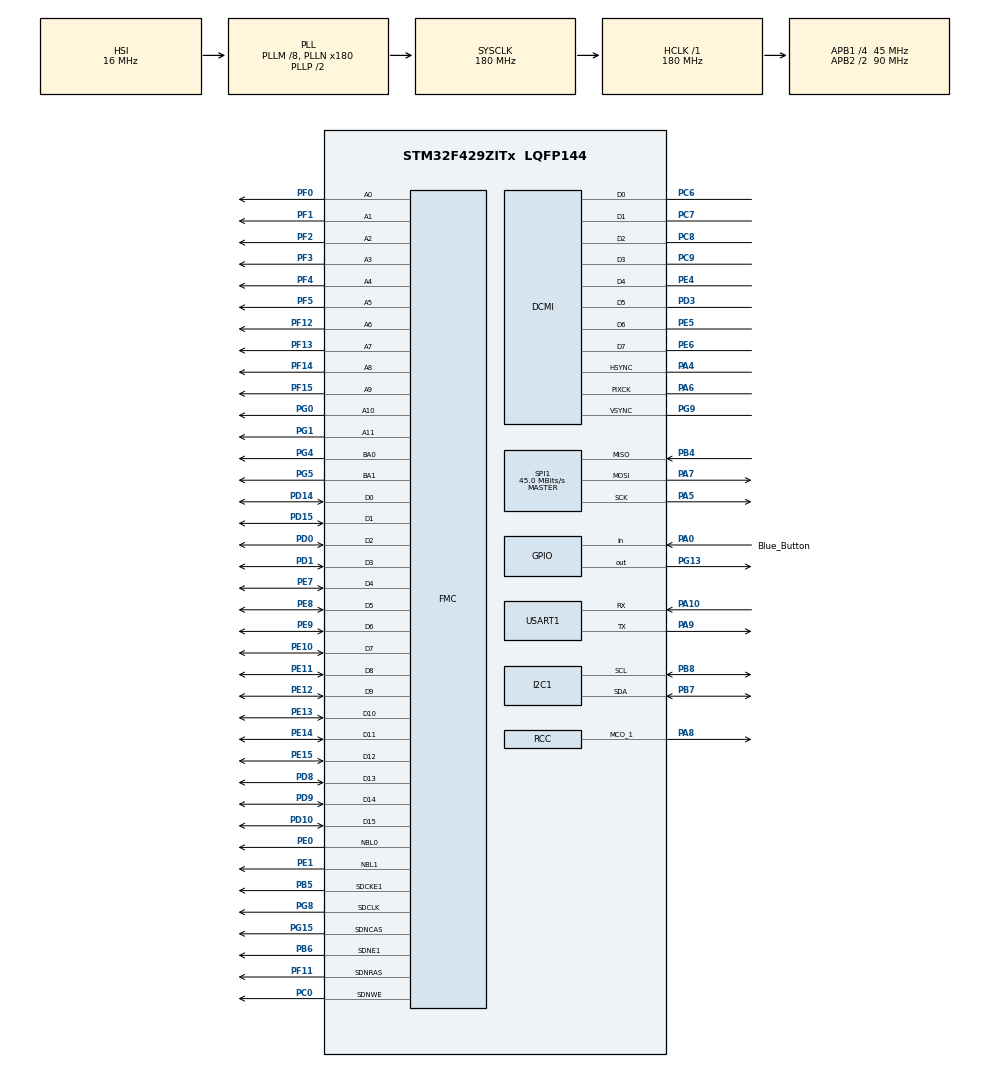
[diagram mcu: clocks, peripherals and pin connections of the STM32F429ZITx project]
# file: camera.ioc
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DCMI.HSPolarity=DCMI_HSPOLARITY_LOW
DCMI.JPEGMode=DCMI_JPEG_DISABLE
DCMI.PCKPolarity=DCMI_PCKPOLARITY_RISING
DCMI.VSPolarity=DCMI_VSPOLARITY_HIGH
Dma.DCMI.0.Direction=DMA_PERIPH_TO_MEMORY
Dma.DCMI.0.FIFOMode=DMA_FIFOMODE_DISABLE
Dma.DCMI.0.Instance=DMA2_Stream1
Dma.DCMI.0.MemDataAlignment=DMA_MDATAALIGN_WORD
Dma.DCMI.0.MemInc=DMA_MINC_ENABLE
Dma.DCMI.0.Mode=DMA_NORMAL
Dma.DCMI.0.PeriphDataAlignment=DMA_PDATAALIGN_WORD
Dma.DCMI.0.PeriphInc=DMA_PINC_DISABLE
Dma.DCMI.0.Priority=DMA_PRIORITY_LOW
Dma.Request0=DCMI
FMC.CASLatency1=FMC_SDRAM_CAS_LATENCY_3
FMC.ExitSelfRefreshDelay1=7
FMC.LoadToActiveDelay1=2
FMC.RCDDelay1=2
FMC.RPDelay1=2
FMC.RPDelay2=2
FMC.ReadPipeDelay1=FMC_SDRAM_RPIPE_DELAY_1
FMC.ReadPipeDelay2=FMC_SDRAM_RPIPE_DELAY_1
FMC.RowCycleDelay1=7
FMC.RowCycleDelay2=7
FMC.SDClockPeriod1=FMC_SDRAM_CLOCK_PERIOD_2
FMC.SDClockPeriod2=FMC_SDRAM_CLOCK_PERIOD_2
FMC.SelfRefreshTime1=4
FMC.WriteRecoveryTime1=3
Mcu.Family=STM32F4
Mcu.Name=STM32F429ZITx
Mcu.Package=LQFP144
NVIC.DCMI_IRQn=true\:0\:0\:false\:false\:true\:true
NVIC.DMA2_Stream1_IRQn=true\:0\:0\:false\:false\:true\:false
NVIC.PriorityGroup=NVIC_PRIORITYGROUP_4
PA0/WKUP.GPIO_Label=Blue_Button
PA0/WKUP.GPIO_PuPd=GPIO_PULLDOWN
PA0/WKUP.Signal=GPIO_Input
PA10.Mode=Asynchronous
PA10.Signal=USART1_RX
PA4.Mode=Slave_8_bits_External_Synchro
PA4.Signal=DCMI_HSYNC
PA5.Mode=Full_Duplex_Master
PA5.Signal=SPI1_SCK
PA6.Mode=Slave_8_bits_External_Synchro
PA6.Signal=DCMI_PIXCK
PA7.Mode=Full_Duplex_Master
PA7.Signal=SPI1_MOSI
PA8.Mode=Clock-out-1
PA8.Signal=RCC_MCO_1
PA9.Mode=Asynchronous
PA9.Signal=USART1_TX
PB4.Mode=Full_Duplex_Master
PB4.Signal=SPI1_MISO
PB5.Mode=SdramChipSelect2_1
PB5.Signal=FMC_SDCKE1
PB6.Mode=SdramChipSelect2_1
PB6.Signal=FMC_SDNE1
PB7.Mode=I2C
PB7.Signal=I2C1_SDA
PB8.Mode=I2C
PB8.Signal=I2C1_SCL
PC0.Signal=FMC_SDNWE
PC6.Mode=Slave_8_bits_External_Synchro
PC6.Signal=DCMI_D0
PC7.Mode=Slave_8_bits_External_Synchro
PC7.Signal=DCMI_D1
PC8.Mode=Slave_8_bits_External_Synchro
PC8.Signal=DCMI_D2
PC9.Mode=Slave_8_bits_External_Synchro
PC9.Signal=DCMI_D3
PD0.Signal=FMC_D2_DA2
PD1.Signal=FMC_D3_DA3
PD10.Signal=FMC_D15_DA15
PD14.Signal=FMC_D0_DA0
PD15.Signal=FMC_D1_DA1
PD3.Mode=Slave_8_bits_External_Synchro
PD3.Signal=DCMI_D5
PD8.Signal=FMC_D13_DA13
PD9.Signal=FMC_D14_DA14
PE0.Signal=FMC_NBL0
PE1.Signal=FMC_NBL1
PE10.Signal=FMC_D7_DA7
PE11.Signal=FMC_D8_DA8
PE12.Signal=FMC_D9_DA9
PE13.Signal=FMC_D10_DA10
PE14.Signal=FMC_D11_DA11
PE15.Signal=FMC_D12_DA12
PE4.Mode=Slave_8_bits_External_Synchro
PE4.Signal=DCMI_D4
PE5.Mode=Slave_8_bits_External_Synchro
PE5.Signal=DCMI_D6
PE6.Mode=Slave_8_bits_External_Synchro
PE6.Signal=DCMI_D7
PE7.Signal=FMC_D4_DA4
PE8.Signal=FMC_D5_DA5
PE9.Signal=FMC_D6_DA6
PF0.Signal=FMC_A0
PF1.Signal=FMC_A1
PF11.Signal=FMC_SDNRAS
PF12.Signal=FMC_A6
PF13.Signal=FMC_A7
PF14.Signal=FMC_A8
PF15.Signal=FMC_A9
PF2.Signal=FMC_A2
PF3.Signal=FMC_A3
PF4.Signal=FMC_A4
PF5.Signal=FMC_A5
PG0.Signal=FMC_A10
PG1.Signal=FMC_A11
PG13.GPIO_PuPd=GPIO_NOPULL
PG13.Signal=GPIO_Output
PG15.Signal=FMC_SDNCAS
PG4.Signal=FMC_A14_BA0
PG5.Signal=FMC_A15_BA1
PG8.Signal=FMC_SDCLK
PG9.Mode=Slave_8_bits_External_Synchro
PG9.Signal=DCMI_VSYNC
ProjectManager.HeapSize=0x200
ProjectManager.StackSize=0x400
ProjectManager.TargetToolchain=TrueSTUDIO
RCC.48MHZClocksFreq_Value=90000000
RCC.AHBFreq_Value=180000000
RCC.APB1CLKDivider=RCC_HCLK_DIV4
RCC.APB1Freq_Value=45000000
RCC.APB1TimFreq_Value=90000000
RCC.APB2CLKDivider=RCC_HCLK_DIV2
RCC.APB2Freq_Value=90000000
RCC.APB2TimFreq_Value=180000000
RCC.CortexFreq_Value=180000000
RCC.HCLKFreq_Value=180000000
RCC.HSE_VALUE=25000000
RCC.HSI_VALUE=16000000
RCC.LSE_VALUE=32768
RCC.PLLM=8
RCC.PLLN=180
RCC.RCC_MCODiv1=RCC_MCODIV_2
RCC.SYSCLKFreq_VALUE=180000000
RCC.SYSCLKSource=RCC_SYSCLKSOURCE_PLLCLK
RCC.VCOOutputFreq_Value=360000000
SH.FMC_A0.0=FMC_A0,12b-sda1
SH.FMC_A1.0=FMC_A1,12b-sda1
SH.FMC_A10.0=FMC_A10,12b-sda1
SH.FMC_A11.0=FMC_A11,12b-sda1
SH.FMC_A14_BA0.0=FMC_BA0,FourSdramBanks1
SH.FMC_A15_BA1.0=FMC_BA1,FourSdramBanks1
SH.FMC_A2.0=FMC_A2,12b-sda1
SH.FMC_A3.0=FMC_A3,12b-sda1
SH.FMC_A4.0=FMC_A4,12b-sda1
SH.FMC_A5.0=FMC_A5,12b-sda1
SH.FMC_A6.0=FMC_A6,12b-sda1
SH.FMC_A7.0=FMC_A7,12b-sda1
SH.FMC_A8.0=FMC_A8,12b-sda1
SH.FMC_A9.0=FMC_A9,12b-sda1
SH.FMC_D0_DA0.0=FMC_D0,sd-16b-d1
SH.FMC_D10_DA10.0=FMC_D10,sd-16b-d1
SH.FMC_D11_DA11.0=FMC_D11,sd-16b-d1
SH.FMC_D12_DA12.0=FMC_D12,sd-16b-d1
SH.FMC_D13_DA13.0=FMC_D13,sd-16b-d1
SH.FMC_D14_DA14.0=FMC_D14,sd-16b-d1
SH.FMC_D15_DA15.0=FMC_D15,sd-16b-d1
SH.FMC_D1_DA1.0=FMC_D1,sd-16b-d1
SH.FMC_D2_DA2.0=FMC_D2,sd-16b-d1
SH.FMC_D3_DA3.0=FMC_D3,sd-16b-d1
SH.FMC_D4_DA4.0=FMC_D4,sd-16b-d1
SH.FMC_D5_DA5.0=FMC_D5,sd-16b-d1
SH.FMC_D6_DA6.0=FMC_D6,sd-16b-d1
SH.FMC_D7_DA7.0=FMC_D7,sd-16b-d1
SH.FMC_D8_DA8.0=FMC_D8,sd-16b-d1
SH.FMC_D9_DA9.0=FMC_D9,sd-16b-d1
SH.FMC_NBL0.0=FMC_NBL0,Sd2ByteEnable1
SH.FMC_NBL1.0=FMC_NBL1,Sd2ByteEnable1
SH.FMC_SDCLK.0=FMC_SDCLK,12b-sda1
SH.FMC_SDNCAS.0=FMC_SDNCAS,12b-sda1
SH.FMC_SDNRAS.0=FMC_SDNRAS,12b-sda1
SH.FMC_SDNWE.0=FMC_SDNWE,12b-sda1
SPI1.CalculateBaudRate=45.0 MBits/s
SPI1.Direction=SPI_DIRECTION_2LINES
SPI1.Mode=SPI_MODE_MASTER
SPI1.VirtualType=VM_MASTER
USART1.VirtualMode=VM_ASYNC
board=custom

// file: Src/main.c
/* USER CODE BEGIN Header */
/**
  ******************************************************************************
  * @file           : main.c
  * @brief          : Main program body
  ******************************************************************************
  ** This notice applies to any and all portions of this file
  * that are not between comment pairs USER CODE BEGIN and
  * USER CODE END. Other portions of this file, whether
  * inserted by the user or by software development tools
  * are owned by their respective copyright owners.
  *
  * COPYRIGHT(c) 2018 STMicroelectronics
  *
  * Redistribution and use in source and binary forms, with or without modification,
  * are permitted provided that the following conditions are met:
  *   1. Redistributions of source code must retain the above copyright notice,
  *      this list of conditions and the following disclaimer.
  *   2. Redistributions in binary form must reproduce the above copyright notice,
  *      this list of conditions and the following disclaimer in the documentation
  *      and/or other materials provided with the distribution.
  *   3. Neither the name of STMicroelectronics nor the names of its contributors
  *      may be used to endorse or promote products derived from this software
  *      without specific prior written permission.
  *
  * THIS SOFTWARE IS PROVIDED BY THE COPYRIGHT HOLDERS AND CONTRIBUTORS "AS IS"
  * AND ANY EXPRESS OR IMPLIED WARRANTIES, INCLUDING, BUT NOT LIMITED TO, THE
  * IMPLIED WARRANTIES OF MERCHANTABILITY AND FITNESS FOR A PARTICULAR PURPOSE ARE
  * DISCLAIMED. IN NO EVENT SHALL THE COPYRIGHT HOLDER OR CONTRIBUTORS BE LIABLE
  * FOR ANY DIRECT, INDIRECT, INCIDENTAL, SPECIAL, EXEMPLARY, OR CONSEQUENTIAL
  * DAMAGES (INCLUDING, BUT NOT LIMITED TO, PROCUREMENT OF SUBSTITUTE GOODS OR
  * SERVICES; LOSS OF USE, DATA, OR PROFITS; OR BUSINESS INTERRUPTION) HOWEVER
  * CAUSED AND ON ANY THEORY OF LIABILITY, WHETHER IN CONTRACT, STRICT LIABILITY,
  * OR TORT (INCLUDING NEGLIGENCE OR OTHERWISE) ARISING IN ANY WAY OUT OF THE USE
  * OF THIS SOFTWARE, EVEN IF ADVISED OF THE POSSIBILITY OF SUCH DAMAGE.
  *
  ******************************************************************************
  */
/* USER CODE END Header */

#include "main.h"

/* USER CODE BEGIN Includes */
#include "ov7670.h"
#include "spi.h"
#include "nrf.h"
#include <string.h>
#include <stdio.h>
#include <stdlib.h>
#include <math.h>
#include "arm_math.h"
#include "parameter.h"
#include "weights.h"
#include "arm_nnfunctions.h"
/* USER CODE END Includes */

/* USER CODE BEGIN PTD */
#define INPUT_MEAN_SHIFT {125,123,114}
#define INPUT_RIGHT_SHIFT {8,8,8}
#define __SSAT(ARG1,ARG2) \
__extension__ \
({                          \
  int32_t __RES, __ARG1 = (ARG1); \
  __ASM ("ssat %0, %1, %2" : "=r" (__RES) :  "I" (ARG2), "r" (__ARG1) ); \
  __RES; \
 })
/* USER CODE END PTD */

DCMI_HandleTypeDef hdcmi;
DMA_HandleTypeDef hdma_dcmi;

I2C_HandleTypeDef hi2c1;

SPI_HandleTypeDef hspi1;

UART_HandleTypeDef huart1;

SDRAM_HandleTypeDef hsdram1;

/* USER CODE BEGIN PV */

static q7_t conv1_wt[CONV1_IN_CH*CONV1_KER_DIM*CONV1_KER_DIM*CONV1_OUT_CH] = CONV1_WT;
static q7_t conv1_bias[CONV1_OUT_CH] = CONV1_BIAS;

static q7_t conv2_wt[CONV2_IN_CH*CONV2_KER_DIM*CONV2_KER_DIM*CONV2_OUT_CH] = CONV2_WT;
static q7_t conv2_bias[CONV2_OUT_CH] = CONV2_BIAS;

static q7_t conv3_wt[CONV3_IN_CH*CONV3_KER_DIM*CONV3_KER_DIM*CONV3_OUT_CH] = CONV3_WT;
static q7_t conv3_bias[CONV3_OUT_CH] = CONV3_BIAS;

static q7_t ip1_wt[IP1_IN_DIM*IP1_OUT_DIM] = IP1_WT;
static q7_t ip1_bias[IP1_OUT_DIM] = IP1_BIAS;

q7_t input_data[DATA_OUT_CH*DATA_OUT_DIM*DATA_OUT_DIM];
q7_t output_data[IP1_OUT_DIM];

q7_t col_buffer[3200];
q7_t scratch_buffer[40960];
float floater_data[10];

void run_nn() {

  q7_t* buffer1 = scratch_buffer;
  q7_t* buffer2 = buffer1 + 32768;
  arm_convolve_HWC_q7_RGB(input_data, CONV1_IN_DIM, CONV1_IN_CH, conv1_wt, CONV1_OUT_CH, CONV1_KER_DIM, CONV1_PAD, CONV1_STRIDE, conv1_bias, CONV1_BIAS_LSHIFT, CONV1_OUT_RSHIFT, buffer1, CONV1_OUT_DIM, (q15_t*)col_buffer, NULL);
  arm_maxpool_q7_HWC(buffer1, POOL1_IN_DIM, POOL1_IN_CH, POOL1_KER_DIM, POOL1_PAD, POOL1_STRIDE, POOL1_OUT_DIM, col_buffer, buffer2);
  arm_relu_q7(buffer2, RELU1_OUT_DIM*RELU1_OUT_DIM*RELU1_OUT_CH);
  arm_convolve_HWC_q7_fast(buffer2, CONV2_IN_DIM, CONV2_IN_CH, conv2_wt, CONV2_OUT_CH, CONV2_KER_DIM, CONV2_PAD, CONV2_STRIDE, conv2_bias, CONV2_BIAS_LSHIFT, CONV2_OUT_RSHIFT, buffer1, CONV2_OUT_DIM, (q15_t*)col_buffer, NULL);
  arm_relu_q7(buffer1, RELU2_OUT_DIM*RELU2_OUT_DIM*RELU2_OUT_CH);
  arm_avepool_q7_HWC(buffer1, POOL2_IN_DIM, POOL2_IN_CH, POOL2_KER_DIM, POOL2_PAD, POOL2_STRIDE, POOL2_OUT_DIM, col_buffer, buffer2);
  arm_convolve_HWC_q7_fast(buffer2, CONV3_IN_DIM, CONV3_IN_CH, conv3_wt, CONV3_OUT_CH, CONV3_KER_DIM, CONV3_PAD, CONV3_STRIDE, conv3_bias, CONV3_BIAS_LSHIFT, CONV3_OUT_RSHIFT, buffer1, CONV3_OUT_DIM, (q15_t*)col_buffer, NULL);
  arm_relu_q7(buffer1, RELU3_OUT_DIM*RELU3_OUT_DIM*RELU3_OUT_CH);
  arm_avepool_q7_HWC(buffer1, POOL3_IN_DIM, POOL3_IN_CH, POOL3_KER_DIM, POOL3_PAD, POOL3_STRIDE, POOL3_OUT_DIM, col_buffer, buffer2);
  arm_fully_connected_q7_opt(buffer2, ip1_wt, IP1_IN_DIM, IP1_OUT_DIM, IP1_BIAS_LSHIFT, IP1_OUT_RSHIFT, ip1_bias, output_data, (q15_t*)col_buffer);
  arm_softmax_q7(output_data, 10, output_data);
}
/* USER CODE END PV */

void SystemClock_Config(void);
static void MX_GPIO_Init(void);
static void MX_DMA_Init(void);
static void MX_DCMI_Init(void);
static void MX_FMC_Init(void);
static void MX_I2C1_Init(void);
static void MX_SPI1_Init(void);
static void MX_USART1_UART_Init(void);
/* USER CODE BEGIN PFP */
int captured = 0;
float32_t image[32*32*3];
static const char *categories[] = {"airplane","automobile","bird","cat","deer","dog", "frog", "horse", "ship", "truck"};
/* USER CODE END PFP */

/* USER CODE BEGIN 0 */
void HAL_DCMI_FrameEventCallback(DCMI_HandleTypeDef *hdcmi)
{
	captured = 1;
	HAL_DCMI_Stop(hdcmi);
}

void RGB_to_q7(uint8_t* image, q7_t* input_data){
	int mean_data[3] = INPUT_MEAN_SHIFT;
	unsigned int scale_data[3] = INPUT_RIGHT_SHIFT;

	for (int i=0;i<32*32*3; i+=3) {
		input_data[i] =   (q7_t)__SSAT( ((((int)image[i]   - mean_data[0])<<7) + (0x1<<(scale_data[0]-1)))
														 >> scale_data[0], 8);
		input_data[i+1] = (q7_t)__SSAT( ((((int)image[i+1] - mean_data[1])<<7) + (0x1<<(scale_data[1]-1)))
														 >> scale_data[1], 8);
		input_data[i+2] = (q7_t)__SSAT( ((((int)image[i+2] - mean_data[2])<<7) + (0x1<<(scale_data[2]-1)))
														 >> scale_data[2], 8);
	}
}

void capture_image(DCMI_HandleTypeDef* hdcmi, uint8_t* image){
	uint16_t data[176 * 144];
	memset(data, 0, sizeof(data)/sizeof(uint16_t));
	captured = 0;
	HAL_DCMI_Start_DMA(hdcmi, DCMI_MODE_CONTINUOUS, (uint32_t) &data, sizeof(data)/4);
	while(!captured);

	// resize image
	uint8_t y;
	uint8_t cb = 0;
	uint8_t cr = 0;
	int k = 0;
	int h = 0;
	int colorOrder;
	float32_t R;
	float32_t G;
	float32_t B;

	for (int i = 0; i < 144; i++){
		colorOrder = 0;
		for (int j = 0; j < 173; j++){
			y = data[k] >> 8;
			// undo Cb Cr sub-sampling
			if (colorOrder % 2 == 0){
				cb = data[k] & 0xff;
			} else {
				cr = data[k] & 0xff;
			}
			// downsampling to 32 x 32 x 3
			if ((i % 4 == 3) && (j % 5 == 4) && (i < 131) && (j < 164)) {
				R = (uint8_t)((float)y + 1.402 * ((float)cr - 128.0));
				G = (uint8_t)((float)y - 0.34414 * ((float)cr - 128) - 0.71414 * ((float)cb - 128));
				B = (uint8_t)((float)y + 1.772 * ((float)cb - 128));
				// saturate RGB
				if (R > 255){
					R = 255;
				} else if (R < 0){
					R = 0;
				}
				if (G > 255){
					G = 255;
				} else if (G < 0){
					G = 0;
				}
				if (B > 255){
					B = 255;
				} else if (B < 0){
					B = 0;
				}
				// the image to feed into the neural network has to be [RGB RGB ...] format
				image[h] = R;
				image[h+1] = G;
				image[h+2] = B;
				h = h + 3;
			}
			k = k + 1;
			colorOrder = colorOrder + 1;
		}
	}
	uint8_t buffer[10];
	memset(buffer, 0, 10);
	for (int i = 0; i < 176*144; i++){
		sprintf(buffer, "%d\r\n", data[i]);
		for(int j=0;j<strlen(buffer);j++)
		{
			HAL_UART_Transmit(&huart1, &buffer[j], 1, 1000);
		}
	}
}
/* USER CODE END 0 */

int main(void)
{
  /* USER CODE BEGIN 1 */
	printf("Hello, world!\n");
  /* USER CODE END 1 */

  /* MCU Configuration--------------------------------------------------------*/

  /* Reset of all peripherals, Initializes the Flash interface and the Systick. */
  HAL_Init();

  /* Configure the system clock */
  SystemClock_Config();

  /* Initialize all configured peripherals */
  MX_GPIO_Init();
  MX_DMA_Init();
  MX_DCMI_Init();
  MX_FMC_Init();
  MX_I2C1_Init();
  MX_SPI1_Init();
  MX_USART1_UART_Init();
  /* USER CODE BEGIN 2 */
  OV7670_init(&hi2c1);
  NRF_init();
  /* USER CODE END 2 */

  /* Infinite loop */
  /* USER CODE BEGIN WHILE */
  while (1)
  {
//  	int max_idx = 0;
//  	char class_text[20];
//		strcpy(class_text, categories[max_idx]);
//		uint8_t class_buffer[20];
//		memset(class_buffer, 0, 20);
//		sprintf(class_buffer, "%s\r\n", class_buffer);
//		// send category string through nRF24L01
//		NRF_transmit(class_buffer, 20);

  	// PA0 is the blue push button
  	if(HAL_GPIO_ReadPin(GPIOA, GPIO_PIN_0) == GPIO_PIN_SET)
  	{
  		// light up LED to indicate recording status
  		HAL_GPIO_WritePin(GPIOG, GPIO_PIN_13, GPIO_PIN_SET);
  		// capture image
  		capture_image(&hdcmi, image);
  		// convert RGB float to q7 bit format
			RGB_to_q7(image, input_data);
			// pass image to neural network
			run_nn();

			// convert q7 bit output to float
			arm_q7_to_float(output_data, floater_data, 10);
			// pick argmax class string from output
			float max_val = -100;
			int max_idx = 0;
			for (int i = 0; i < 10; i++){
				if (floater_data[i] > max_val){
					max_val = floater_data[i];
					max_idx = i;
				}
			}
			char class_text[20];
			strcpy(class_text, categories[max_idx]);
			uint8_t class_buffer[20];
			memset(class_buffer, 0, 20);
			sprintf(class_buffer, "%s", class_text);
			// send category string through nRF24L01
			NRF_transmit(class_buffer, 20);
  	}
  	else
  	{
  		HAL_GPIO_WritePin(GPIOG, GPIO_PIN_13, GPIO_PIN_RESET);
  	}

    /* USER CODE END WHILE */

  }
}

void SystemClock_Config(void)
{
  RCC_OscInitTypeDef RCC_OscInitStruct = {0};
  RCC_ClkInitTypeDef RCC_ClkInitStruct = {0};

  /**Configure the main internal regulator output voltage
  */
  __HAL_RCC_PWR_CLK_ENABLE();
  __HAL_PWR_VOLTAGESCALING_CONFIG(PWR_REGULATOR_VOLTAGE_SCALE1);
  /**Initializes the CPU, AHB and APB busses clocks
  */
  RCC_OscInitStruct.OscillatorType = RCC_OSCILLATORTYPE_HSI;
  RCC_OscInitStruct.HSIState = RCC_HSI_ON;
  RCC_OscInitStruct.HSICalibrationValue = RCC_HSICALIBRATION_DEFAULT;
  RCC_OscInitStruct.PLL.PLLState = RCC_PLL_ON;
  RCC_OscInitStruct.PLL.PLLSource = RCC_PLLSOURCE_HSI;
  RCC_OscInitStruct.PLL.PLLM = 8;
  RCC_OscInitStruct.PLL.PLLN = 180;
  RCC_OscInitStruct.PLL.PLLP = RCC_PLLP_DIV2;
  RCC_OscInitStruct.PLL.PLLQ = 4;
  if (HAL_RCC_OscConfig(&RCC_OscInitStruct) != HAL_OK)
  {
    Error_Handler();
  }
  /**Activate the Over-Drive mode
  */
  if (HAL_PWREx_EnableOverDrive() != HAL_OK)
  {
    Error_Handler();
  }
  /**Initializes the CPU, AHB and APB busses clocks
  */
  RCC_ClkInitStruct.ClockType = RCC_CLOCKTYPE_HCLK|RCC_CLOCKTYPE_SYSCLK
                              |RCC_CLOCKTYPE_PCLK1|RCC_CLOCKTYPE_PCLK2;
  RCC_ClkInitStruct.SYSCLKSource = RCC_SYSCLKSOURCE_PLLCLK;
  RCC_ClkInitStruct.AHBCLKDivider = RCC_SYSCLK_DIV1;
  RCC_ClkInitStruct.APB1CLKDivider = RCC_HCLK_DIV4;
  RCC_ClkInitStruct.APB2CLKDivider = RCC_HCLK_DIV2;

  if (HAL_RCC_ClockConfig(&RCC_ClkInitStruct, FLASH_LATENCY_5) != HAL_OK)
  {
    Error_Handler();
  }
  HAL_RCC_MCOConfig(RCC_MCO1, RCC_MCO1SOURCE_HSI, RCC_MCODIV_2);
}

static void MX_DCMI_Init(void)
{

  hdcmi.Instance = DCMI;
  hdcmi.Init.SynchroMode = DCMI_SYNCHRO_HARDWARE;
  hdcmi.Init.PCKPolarity = DCMI_PCKPOLARITY_RISING;
  hdcmi.Init.VSPolarity = DCMI_VSPOLARITY_HIGH;
  hdcmi.Init.HSPolarity = DCMI_HSPOLARITY_LOW;
  hdcmi.Init.CaptureRate = DCMI_CR_ALL_FRAME;
  hdcmi.Init.ExtendedDataMode = DCMI_EXTEND_DATA_8B;
  hdcmi.Init.JPEGMode = DCMI_JPEG_DISABLE;
  if (HAL_DCMI_Init(&hdcmi) != HAL_OK)
  {
    Error_Handler();
  }

}

static void MX_I2C1_Init(void)
{

  hi2c1.Instance = I2C1;
  hi2c1.Init.ClockSpeed = 100000;
  hi2c1.Init.DutyCycle = I2C_DUTYCYCLE_2;
  hi2c1.Init.OwnAddress1 = 0;
  hi2c1.Init.AddressingMode = I2C_ADDRESSINGMODE_7BIT;
  hi2c1.Init.DualAddressMode = I2C_DUALADDRESS_DISABLE;
  hi2c1.Init.OwnAddress2 = 0;
  hi2c1.Init.GeneralCallMode = I2C_GENERALCALL_DISABLE;
  hi2c1.Init.NoStretchMode = I2C_NOSTRETCH_DISABLE;
  if (HAL_I2C_Init(&hi2c1) != HAL_OK)
  {
    Error_Handler();
  }
  /**Configure Analogue filter
  */
  if (HAL_I2CEx_ConfigAnalogFilter(&hi2c1, I2C_ANALOGFILTER_ENABLE) != HAL_OK)
  {
    Error_Handler();
  }
  /**Configure Digital filter
  */
  if (HAL_I2CEx_ConfigDigitalFilter(&hi2c1, 0) != HAL_OK)
  {
    Error_Handler();
  }

}

static void MX_SPI1_Init(void)
{

  /* SPI1 parameter configuration*/
  hspi1.Instance = SPI1;
  hspi1.Init.Mode = SPI_MODE_MASTER;
  hspi1.Init.Direction = SPI_DIRECTION_2LINES;
  hspi1.Init.DataSize = SPI_DATASIZE_8BIT;
  hspi1.Init.CLKPolarity = SPI_POLARITY_LOW;
  hspi1.Init.CLKPhase = SPI_PHASE_1EDGE;
  hspi1.Init.NSS = SPI_NSS_SOFT;
  hspi1.Init.BaudRatePrescaler = SPI_BAUDRATEPRESCALER_16;
  hspi1.Init.FirstBit = SPI_FIRSTBIT_MSB;
  hspi1.Init.TIMode = SPI_TIMODE_DISABLE;
  hspi1.Init.CRCCalculation = SPI_CRCCALCULATION_DISABLE;
  hspi1.Init.CRCPolynomial = 10;
  if (HAL_SPI_Init(&hspi1) != HAL_OK)
  {
    Error_Handler();
  }

}

static void MX_USART1_UART_Init(void)
{

  huart1.Instance = USART1;
  huart1.Init.BaudRate = 115200;
  huart1.Init.WordLength = UART_WORDLENGTH_8B;
  huart1.Init.StopBits = UART_STOPBITS_1;
  huart1.Init.Parity = UART_PARITY_NONE;
  huart1.Init.Mode = UART_MODE_TX_RX;
  huart1.Init.HwFlowCtl = UART_HWCONTROL_NONE;
  huart1.Init.OverSampling = UART_OVERSAMPLING_16;
  if (HAL_UART_Init(&huart1) != HAL_OK)
  {
    Error_Handler();
  }

}

static void MX_DMA_Init(void)
{
  /* DMA controller clock enable */
  __HAL_RCC_DMA2_CLK_ENABLE();

  /* DMA interrupt init */
  /* DMA2_Stream1_IRQn interrupt configuration */
  HAL_NVIC_SetPriority(DMA2_Stream1_IRQn, 0, 0);
  HAL_NVIC_EnableIRQ(DMA2_Stream1_IRQn);

}
/* FMC initialization function */
static void MX_FMC_Init(void)
{
  FMC_SDRAM_TimingTypeDef SdramTiming;

  /** Perform the SDRAM1 memory initialization sequence
  */
  hsdram1.Instance = FMC_SDRAM_DEVICE;
  /* hsdram1.Init */
  hsdram1.Init.SDBank = FMC_SDRAM_BANK2;
  hsdram1.Init.ColumnBitsNumber = FMC_SDRAM_COLUMN_BITS_NUM_8;
  hsdram1.Init.RowBitsNumber = FMC_SDRAM_ROW_BITS_NUM_12;
  hsdram1.Init.MemoryDataWidth = FMC_SDRAM_MEM_BUS_WIDTH_16;
  hsdram1.Init.InternalBankNumber = FMC_SDRAM_INTERN_BANKS_NUM_4;
  hsdram1.Init.CASLatency = FMC_SDRAM_CAS_LATENCY_3;
  hsdram1.Init.WriteProtection = FMC_SDRAM_WRITE_PROTECTION_DISABLE;
  hsdram1.Init.SDClockPeriod = FMC_SDRAM_CLOCK_PERIOD_2;
  hsdram1.Init.ReadBurst = FMC_SDRAM_RBURST_DISABLE;
  hsdram1.Init.ReadPipeDelay = FMC_SDRAM_RPIPE_DELAY_1;
  /* SdramTiming */
  SdramTiming.LoadToActiveDelay = 2;
  SdramTiming.ExitSelfRefreshDelay = 7;
  SdramTiming.SelfRefreshTime = 4;
  SdramTiming.RowCycleDelay = 7;
  SdramTiming.WriteRecoveryTime = 3;
  SdramTiming.RPDelay = 2;
  SdramTiming.RCDDelay = 2;

  if (HAL_SDRAM_Init(&hsdram1, &SdramTiming) != HAL_OK)
  {
    Error_Handler( );
  }

}

static void MX_GPIO_Init(void)
{
  GPIO_InitTypeDef GPIO_InitStruct = {0};

  /* GPIO Ports Clock Enable */
  __HAL_RCC_GPIOE_CLK_ENABLE();
  __HAL_RCC_GPIOF_CLK_ENABLE();
  __HAL_RCC_GPIOC_CLK_ENABLE();
  __HAL_RCC_GPIOA_CLK_ENABLE();
  __HAL_RCC_GPIOG_CLK_ENABLE();
  __HAL_RCC_GPIOD_CLK_ENABLE();
  __HAL_RCC_GPIOB_CLK_ENABLE();

  /*Configure GPIO pin Output Level */
  HAL_GPIO_WritePin(GPIOC, SPI_CE_Pin|SPI_CSN_Pin, GPIO_PIN_RESET);

  /*Configure GPIO pin Output Level */
  HAL_GPIO_WritePin(GPIOG, GPIO_PIN_13, GPIO_PIN_RESET);

  /*Configure GPIO pin : Blue_Button_Pin */
  GPIO_InitStruct.Pin = Blue_Button_Pin;
  GPIO_InitStruct.Mode = GPIO_MODE_INPUT;
  GPIO_InitStruct.Pull = GPIO_PULLDOWN;
  HAL_GPIO_Init(Blue_Button_GPIO_Port, &GPIO_InitStruct);

  /*Configure GPIO pins : SPI_CE_Pin SPI_CSN_Pin */
  GPIO_InitStruct.Pin = SPI_CE_Pin|SPI_CSN_Pin;
  GPIO_InitStruct.Mode = GPIO_MODE_OUTPUT_PP;
  GPIO_InitStruct.Pull = GPIO_NOPULL;
  GPIO_InitStruct.Speed = GPIO_SPEED_FREQ_LOW;
  HAL_GPIO_Init(GPIOC, &GPIO_InitStruct);

  /*Configure GPIO pin : PA8 */
  GPIO_InitStruct.Pin = GPIO_PIN_8;
  GPIO_InitStruct.Mode = GPIO_MODE_AF_PP;
  GPIO_InitStruct.Pull = GPIO_NOPULL;
  GPIO_InitStruct.Speed = GPIO_SPEED_FREQ_LOW;
  GPIO_InitStruct.Alternate = GPIO_AF0_MCO;
  HAL_GPIO_Init(GPIOA, &GPIO_InitStruct);

  /*Configure GPIO pin : PG13 */
  GPIO_InitStruct.Pin = GPIO_PIN_13;
  GPIO_InitStruct.Mode = GPIO_MODE_OUTPUT_PP;
  GPIO_InitStruct.Pull = GPIO_NOPULL;
  GPIO_InitStruct.Speed = GPIO_SPEED_FREQ_LOW;
  HAL_GPIO_Init(GPIOG, &GPIO_InitStruct);

}

void Error_Handler(void)
{
}

/************************ (C) COPYRIGHT STMicroelectronics *****END OF FILE****/
